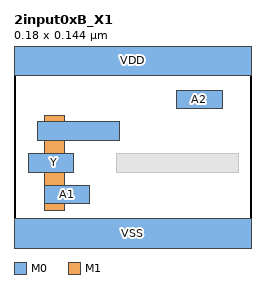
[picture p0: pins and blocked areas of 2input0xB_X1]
MACRO 2input0xB_X1
  CLASS CORE ;
  ORIGIN 0 0 ;
  FOREIGN 2input0xB_X1 0 0 ;
  SIZE 0.1800 BY 0.1440 ;
  SYMMETRY X Y ;
  SITE coresite ;
  PIN A1
    DIRECTION INPUT ;
    USE SIGNAL ;
    PORT
      LAYER M0 ;
        RECT 0.0230 0.0290 0.0570 0.0430 ;
    END
  END A1
  PIN A2
    DIRECTION INPUT ;
    USE SIGNAL ;
    PORT
      LAYER M0 ;
        RECT 0.1230 0.1010 0.1580 0.1150 ;
    END
  END A2
  PIN Y
    DIRECTION OUTPUT ;
    USE SIGNAL ;
    PORT
      LAYER M1 ;
        RECT 0.0230 0.0240 0.0380 0.0960 ;
      LAYER M0 ;
        RECT 0.0180 0.0770 0.0800 0.0910 ;
        RECT 0.0110 0.0530 0.0450 0.0670 ;
    END
  END Y
  PIN VDD
    DIRECTION INOUT ;
    USE POWER ;
    SHAPE ABUTMENT ;
    PORT
      LAYER M0 ;
        RECT 0.0000 0.1260 0.1800 0.1620 ;
    END
  END VDD
  PIN VSS
    DIRECTION INOUT ;
    USE GROUND ;
    SHAPE ABUTMENT ;
    PORT
      LAYER M0 ;
        RECT 0.0000 -0.0180 0.1800 0.0180 ;
    END
  END VSS
  OBS
    LAYER V0 ;
      RECT 0.0230 0.0770 0.0370 0.0910 ;
      RECT 0.0230 0.0530 0.0370 0.0670 ;
    LAYER M0 ;
      RECT 0.0780 0.0530 0.1700 0.0670 ;
  END
END 2input0xB_X1
